VERSION 5.7 ;
  NOWIREEXTENSIONATPIN ON ;
  DIVIDERCHAR "/" ;
  BUSBITCHARS "[]" ;
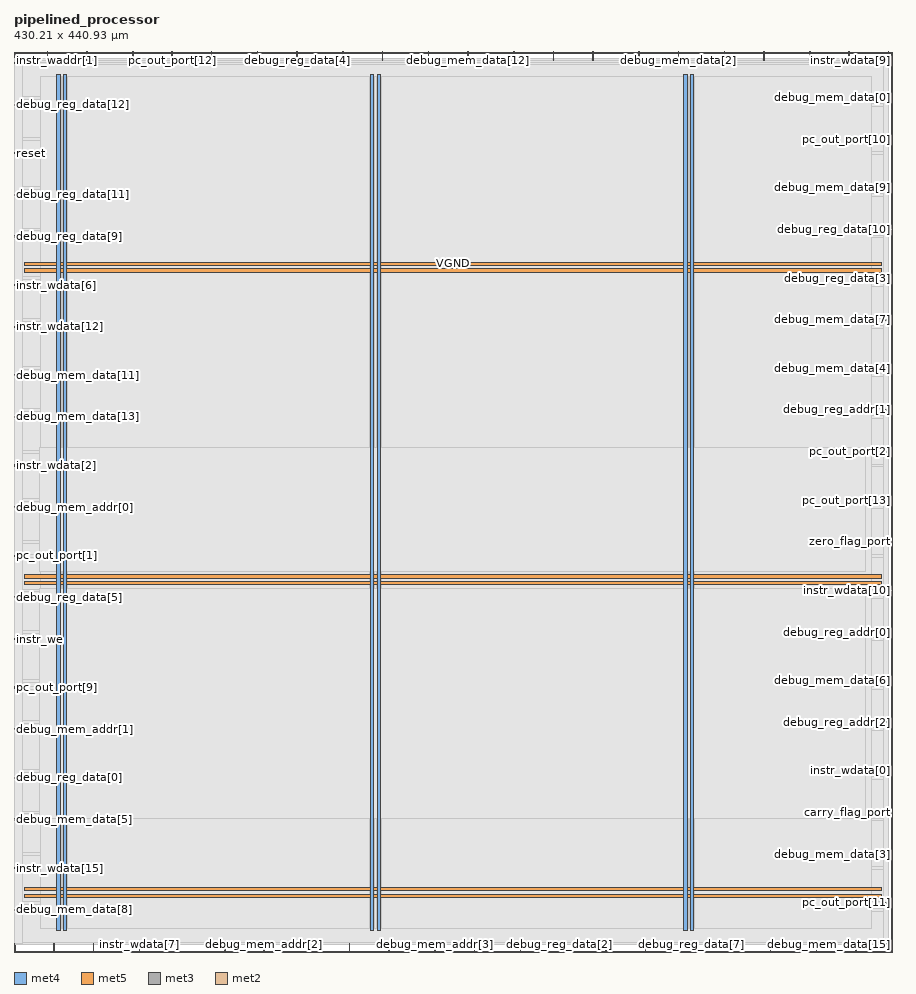
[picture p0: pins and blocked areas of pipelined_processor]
MACRO pipelined_processor
  CLASS BLOCK ;
  FOREIGN pipelined_processor ;
  ORIGIN 0.000 0.000 ;
  SIZE 430.210 BY 440.930 ;
  PIN VGND
    DIRECTION INOUT ;
    USE GROUND ;
    PORT
      LAYER met4 ;
        RECT 24.340 10.640 25.940 430.000 ;
    END
    PORT
      LAYER met4 ;
        RECT 177.940 10.640 179.540 430.000 ;
    END
    PORT
      LAYER met4 ;
        RECT 331.540 10.640 333.140 430.000 ;
    END
    PORT
      LAYER met5 ;
        RECT 5.280 30.030 424.820 31.630 ;
    END
    PORT
      LAYER met5 ;
        RECT 5.280 183.210 424.820 184.810 ;
    END
    PORT
      LAYER met5 ;
        RECT 5.280 336.390 424.820 337.990 ;
    END
  END VGND
  PIN VPWR
    DIRECTION INOUT ;
    USE POWER ;
    PORT
      LAYER met4 ;
        RECT 21.040 10.640 22.640 430.000 ;
    END
    PORT
      LAYER met4 ;
        RECT 174.640 10.640 176.240 430.000 ;
    END
    PORT
      LAYER met4 ;
        RECT 328.240 10.640 329.840 430.000 ;
    END
    PORT
      LAYER met5 ;
        RECT 5.280 26.730 424.820 28.330 ;
    END
    PORT
      LAYER met5 ;
        RECT 5.280 179.910 424.820 181.510 ;
    END
    PORT
      LAYER met5 ;
        RECT 5.280 333.090 424.820 334.690 ;
    END
  END VPWR
  PIN carry_flag_port
    DIRECTION OUTPUT TRISTATE ;
    USE SIGNAL ;
    ANTENNADIFFAREA 0.795200 ;
    PORT
      LAYER met3 ;
        RECT 426.210 68.040 430.210 68.640 ;
    END
  END carry_flag_port
  PIN clk
    DIRECTION INPUT ;
    USE SIGNAL ;
    ANTENNAGATEAREA 1.286700 ;
    ANTENNADIFFAREA 0.434700 ;
    PORT
      LAYER met2 ;
        RECT 389.710 436.930 389.990 440.930 ;
    END
  END clk
  PIN debug_mem_addr[0]
    DIRECTION INPUT ;
    USE SIGNAL ;
    ANTENNAGATEAREA 0.159000 ;
    PORT
      LAYER met3 ;
        RECT 0.000 217.640 4.000 218.240 ;
    END
  END debug_mem_addr[0]
  PIN debug_mem_addr[1]
    DIRECTION INPUT ;
    USE SIGNAL ;
    ANTENNAGATEAREA 0.213000 ;
    PORT
      LAYER met3 ;
        RECT 0.000 108.840 4.000 109.440 ;
    END
  END debug_mem_addr[1]
  PIN debug_mem_addr[2]
    DIRECTION INPUT ;
    USE SIGNAL ;
    ANTENNAGATEAREA 0.159000 ;
    PORT
      LAYER met2 ;
        RECT 122.450 0.000 122.730 4.000 ;
    END
  END debug_mem_addr[2]
  PIN debug_mem_addr[3]
    DIRECTION INPUT ;
    USE SIGNAL ;
    ANTENNAGATEAREA 0.159000 ;
    PORT
      LAYER met2 ;
        RECT 206.170 0.000 206.450 4.000 ;
    END
  END debug_mem_addr[3]
  PIN debug_mem_addr[4]
    DIRECTION INPUT ;
    USE SIGNAL ;
    ANTENNAGATEAREA 0.213000 ;
    PORT
      LAYER met2 ;
        RECT 351.070 0.000 351.350 4.000 ;
    END
  END debug_mem_addr[4]
  PIN debug_mem_addr[5]
    DIRECTION INPUT ;
    USE SIGNAL ;
    ANTENNAGATEAREA 0.159000 ;
    PORT
      LAYER met2 ;
        RECT 370.390 0.000 370.670 4.000 ;
    END
  END debug_mem_addr[5]
  PIN debug_mem_data[0]
    DIRECTION OUTPUT TRISTATE ;
    USE SIGNAL ;
    ANTENNADIFFAREA 0.445500 ;
    PORT
      LAYER met3 ;
        RECT 426.210 418.240 430.210 418.840 ;
    END
  END debug_mem_data[0]
  PIN debug_mem_data[10]
    DIRECTION OUTPUT TRISTATE ;
    USE SIGNAL ;
    ANTENNADIFFAREA 0.445500 ;
    PORT
      LAYER met2 ;
        RECT 58.050 436.930 58.330 440.930 ;
    END
  END debug_mem_data[10]
  PIN debug_mem_data[11]
    DIRECTION OUTPUT TRISTATE ;
    USE SIGNAL ;
    ANTENNADIFFAREA 0.795200 ;
    PORT
      LAYER met3 ;
        RECT 0.000 282.240 4.000 282.840 ;
    END
  END debug_mem_data[11]
  PIN debug_mem_data[12]
    DIRECTION OUTPUT TRISTATE ;
    USE SIGNAL ;
    ANTENNADIFFAREA 0.795200 ;
    PORT
      LAYER met2 ;
        RECT 222.270 436.930 222.550 440.930 ;
    END
  END debug_mem_data[12]
  PIN debug_mem_data[13]
    DIRECTION OUTPUT TRISTATE ;
    USE SIGNAL ;
    ANTENNADIFFAREA 0.795200 ;
    PORT
      LAYER met3 ;
        RECT 0.000 261.840 4.000 262.440 ;
    END
  END debug_mem_data[13]
  PIN debug_mem_data[14]
    DIRECTION OUTPUT TRISTATE ;
    USE SIGNAL ;
    ANTENNADIFFAREA 0.795200 ;
    PORT
      LAYER met3 ;
        RECT 426.210 3.440 430.210 4.040 ;
    END
  END debug_mem_data[14]
  PIN debug_mem_data[15]
    DIRECTION OUTPUT TRISTATE ;
    USE SIGNAL ;
    ANTENNADIFFAREA 0.795200 ;
    PORT
      LAYER met2 ;
        RECT 412.250 0.000 412.530 4.000 ;
    END
  END debug_mem_data[15]
  PIN debug_mem_data[1]
    DIRECTION OUTPUT TRISTATE ;
    USE SIGNAL ;
    ANTENNADIFFAREA 0.445500 ;
    PORT
      LAYER met2 ;
        RECT 244.810 436.930 245.090 440.930 ;
    END
  END debug_mem_data[1]
  PIN debug_mem_data[2]
    DIRECTION OUTPUT TRISTATE ;
    USE SIGNAL ;
    ANTENNADIFFAREA 0.795200 ;
    PORT
      LAYER met2 ;
        RECT 325.310 436.930 325.590 440.930 ;
    END
  END debug_mem_data[2]
  PIN debug_mem_data[3]
    DIRECTION OUTPUT TRISTATE ;
    USE SIGNAL ;
    ANTENNADIFFAREA 0.795200 ;
    PORT
      LAYER met3 ;
        RECT 426.210 47.640 430.210 48.240 ;
    END
  END debug_mem_data[3]
  PIN debug_mem_data[4]
    DIRECTION OUTPUT TRISTATE ;
    USE SIGNAL ;
    ANTENNADIFFAREA 0.445500 ;
    PORT
      LAYER met3 ;
        RECT 426.210 285.640 430.210 286.240 ;
    END
  END debug_mem_data[4]
  PIN debug_mem_data[5]
    DIRECTION OUTPUT TRISTATE ;
    USE SIGNAL ;
    ANTENNADIFFAREA 0.795200 ;
    PORT
      LAYER met3 ;
        RECT 0.000 64.640 4.000 65.240 ;
    END
  END debug_mem_data[5]
  PIN debug_mem_data[6]
    DIRECTION OUTPUT TRISTATE ;
    USE SIGNAL ;
    ANTENNADIFFAREA 0.795200 ;
    PORT
      LAYER met3 ;
        RECT 426.210 132.640 430.210 133.240 ;
    END
  END debug_mem_data[6]
  PIN debug_mem_data[7]
    DIRECTION OUTPUT TRISTATE ;
    USE SIGNAL ;
    ANTENNADIFFAREA 0.795200 ;
    PORT
      LAYER met3 ;
        RECT 426.210 309.440 430.210 310.040 ;
    END
  END debug_mem_data[7]
  PIN debug_mem_data[8]
    DIRECTION OUTPUT TRISTATE ;
    USE SIGNAL ;
    ANTENNADIFFAREA 0.795200 ;
    PORT
      LAYER met3 ;
        RECT 0.000 20.440 4.000 21.040 ;
    END
  END debug_mem_data[8]
  PIN debug_mem_data[9]
    DIRECTION OUTPUT TRISTATE ;
    USE SIGNAL ;
    ANTENNADIFFAREA 0.445500 ;
    PORT
      LAYER met3 ;
        RECT 426.210 374.040 430.210 374.640 ;
    END
  END debug_mem_data[9]
  PIN debug_reg_addr[0]
    DIRECTION INPUT ;
    USE SIGNAL ;
    ANTENNAGATEAREA 0.213000 ;
    PORT
      LAYER met3 ;
        RECT 426.210 156.440 430.210 157.040 ;
    END
  END debug_reg_addr[0]
  PIN debug_reg_addr[1]
    DIRECTION INPUT ;
    USE SIGNAL ;
    ANTENNAGATEAREA 0.213000 ;
    PORT
      LAYER met3 ;
        RECT 426.210 265.240 430.210 265.840 ;
    END
  END debug_reg_addr[1]
  PIN debug_reg_addr[2]
    DIRECTION INPUT ;
    USE SIGNAL ;
    ANTENNAGATEAREA 0.247500 ;
    PORT
      LAYER met3 ;
        RECT 426.210 112.240 430.210 112.840 ;
    END
  END debug_reg_addr[2]
  PIN debug_reg_data[0]
    DIRECTION OUTPUT TRISTATE ;
    USE SIGNAL ;
    ANTENNADIFFAREA 0.795200 ;
    PORT
      LAYER met3 ;
        RECT 0.000 85.040 4.000 85.640 ;
    END
  END debug_reg_data[0]
  PIN debug_reg_data[10]
    DIRECTION OUTPUT TRISTATE ;
    USE SIGNAL ;
    ANTENNADIFFAREA 0.445500 ;
    PORT
      LAYER met3 ;
        RECT 426.210 353.640 430.210 354.240 ;
    END
  END debug_reg_data[10]
  PIN debug_reg_data[11]
    DIRECTION OUTPUT TRISTATE ;
    USE SIGNAL ;
    ANTENNADIFFAREA 0.795200 ;
    PORT
      LAYER met3 ;
        RECT 0.000 370.640 4.000 371.240 ;
    END
  END debug_reg_data[11]
  PIN debug_reg_data[12]
    DIRECTION OUTPUT TRISTATE ;
    USE SIGNAL ;
    ANTENNADIFFAREA 0.795200 ;
    PORT
      LAYER met3 ;
        RECT 0.000 414.840 4.000 415.440 ;
    END
  END debug_reg_data[12]
  PIN debug_reg_data[13]
    DIRECTION OUTPUT TRISTATE ;
    USE SIGNAL ;
    ANTENNADIFFAREA 0.795200 ;
    PORT
      LAYER met3 ;
        RECT 0.000 435.240 4.000 435.840 ;
    END
  END debug_reg_data[13]
  PIN debug_reg_data[14]
    DIRECTION OUTPUT TRISTATE ;
    USE SIGNAL ;
    ANTENNADIFFAREA 0.795200 ;
    PORT
      LAYER met2 ;
        RECT 38.730 0.000 39.010 4.000 ;
    END
  END debug_reg_data[14]
  PIN debug_reg_data[15]
    DIRECTION OUTPUT TRISTATE ;
    USE SIGNAL ;
    ANTENNADIFFAREA 0.795200 ;
    PORT
      LAYER met2 ;
        RECT 264.130 436.930 264.410 440.930 ;
    END
  END debug_reg_data[15]
  PIN debug_reg_data[1]
    DIRECTION OUTPUT TRISTATE ;
    USE SIGNAL ;
    ANTENNADIFFAREA 0.795200 ;
    PORT
      LAYER met2 ;
        RECT 164.310 0.000 164.590 4.000 ;
    END
  END debug_reg_data[1]
  PIN debug_reg_data[2]
    DIRECTION OUTPUT TRISTATE ;
    USE SIGNAL ;
    ANTENNADIFFAREA 0.795200 ;
    PORT
      LAYER met2 ;
        RECT 267.350 0.000 267.630 4.000 ;
    END
  END debug_reg_data[2]
  PIN debug_reg_data[3]
    DIRECTION OUTPUT TRISTATE ;
    USE SIGNAL ;
    ANTENNADIFFAREA 0.445500 ;
    PORT
      LAYER met3 ;
        RECT 426.210 329.840 430.210 330.440 ;
    END
  END debug_reg_data[3]
  PIN debug_reg_data[4]
    DIRECTION OUTPUT TRISTATE ;
    USE SIGNAL ;
    ANTENNADIFFAREA 0.795200 ;
    PORT
      LAYER met2 ;
        RECT 138.550 436.930 138.830 440.930 ;
    END
  END debug_reg_data[4]
  PIN debug_reg_data[5]
    DIRECTION OUTPUT TRISTATE ;
    USE SIGNAL ;
    ANTENNADIFFAREA 0.795200 ;
    PORT
      LAYER met3 ;
        RECT 0.000 173.440 4.000 174.040 ;
    END
  END debug_reg_data[5]
  PIN debug_reg_data[6]
    DIRECTION OUTPUT TRISTATE ;
    USE SIGNAL ;
    ANTENNADIFFAREA 0.795200 ;
    PORT
      LAYER met2 ;
        RECT 103.130 0.000 103.410 4.000 ;
    END
  END debug_reg_data[6]
  PIN debug_reg_data[7]
    DIRECTION OUTPUT TRISTATE ;
    USE SIGNAL ;
    ANTENNADIFFAREA 0.795200 ;
    PORT
      LAYER met2 ;
        RECT 331.750 0.000 332.030 4.000 ;
    END
  END debug_reg_data[7]
  PIN debug_reg_data[8]
    DIRECTION OUTPUT TRISTATE ;
    USE SIGNAL ;
    ANTENNADIFFAREA 0.445500 ;
    PORT
      LAYER met2 ;
        RECT 305.990 436.930 306.270 440.930 ;
    END
  END debug_reg_data[8]
  PIN debug_reg_data[9]
    DIRECTION OUTPUT TRISTATE ;
    USE SIGNAL ;
    ANTENNADIFFAREA 0.795200 ;
    PORT
      LAYER met3 ;
        RECT 0.000 350.240 4.000 350.840 ;
    END
  END debug_reg_data[9]
  PIN instr_waddr[0]
    DIRECTION INPUT ;
    USE SIGNAL ;
    ANTENNAGATEAREA 0.213000 ;
    PORT
      LAYER met2 ;
        RECT 248.030 0.000 248.310 4.000 ;
    END
  END instr_waddr[0]
  PIN instr_waddr[1]
    DIRECTION INPUT ;
    USE SIGNAL ;
    ANTENNAGATEAREA 0.159000 ;
    PORT
      LAYER met2 ;
        RECT 16.190 436.930 16.470 440.930 ;
    END
  END instr_waddr[1]
  PIN instr_waddr[2]
    DIRECTION INPUT ;
    USE SIGNAL ;
    ANTENNAGATEAREA 0.426000 ;
    PORT
      LAYER met2 ;
        RECT 392.930 0.000 393.210 4.000 ;
    END
  END instr_waddr[2]
  PIN instr_waddr[3]
    DIRECTION INPUT ;
    USE SIGNAL ;
    ANTENNAGATEAREA 0.213000 ;
    PORT
      LAYER met2 ;
        RECT 161.090 436.930 161.370 440.930 ;
    END
  END instr_waddr[3]
  PIN instr_wdata[0]
    DIRECTION INPUT ;
    USE SIGNAL ;
    ANTENNAGATEAREA 0.126000 ;
    PORT
      LAYER met3 ;
        RECT 426.210 88.440 430.210 89.040 ;
    END
  END instr_wdata[0]
  PIN instr_wdata[10]
    DIRECTION INPUT ;
    USE SIGNAL ;
    ANTENNAGATEAREA 0.126000 ;
    PORT
      LAYER met3 ;
        RECT 426.210 176.840 430.210 177.440 ;
    END
  END instr_wdata[10]
  PIN instr_wdata[11]
    DIRECTION INPUT ;
    USE SIGNAL ;
    ANTENNAGATEAREA 0.126000 ;
    PORT
      LAYER met2 ;
        RECT 309.210 0.000 309.490 4.000 ;
    END
  END instr_wdata[11]
  PIN instr_wdata[12]
    DIRECTION INPUT ;
    USE SIGNAL ;
    ANTENNAGATEAREA 0.126000 ;
    PORT
      LAYER met3 ;
        RECT 0.000 306.040 4.000 306.640 ;
    END
  END instr_wdata[12]
  PIN instr_wdata[13]
    DIRECTION INPUT ;
    USE SIGNAL ;
    ANTENNAGATEAREA 0.126000 ;
    PORT
      LAYER met2 ;
        RECT 119.230 436.930 119.510 440.930 ;
    END
  END instr_wdata[13]
  PIN instr_wdata[14]
    DIRECTION INPUT ;
    USE SIGNAL ;
    ANTENNAGATEAREA 0.126000 ;
    PORT
      LAYER met2 ;
        RECT 202.950 436.930 203.230 440.930 ;
    END
  END instr_wdata[14]
  PIN instr_wdata[15]
    DIRECTION INPUT ;
    USE SIGNAL ;
    ANTENNAGATEAREA 0.126000 ;
    PORT
      LAYER met3 ;
        RECT 0.000 40.840 4.000 41.440 ;
    END
  END instr_wdata[15]
  PIN instr_wdata[1]
    DIRECTION INPUT ;
    USE SIGNAL ;
    ANTENNAGATEAREA 0.126000 ;
    PORT
      LAYER met2 ;
        RECT 0.090 0.000 0.370 4.000 ;
    END
  END instr_wdata[1]
  PIN instr_wdata[2]
    DIRECTION INPUT ;
    USE SIGNAL ;
    ANTENNAGATEAREA 0.126000 ;
    PORT
      LAYER met3 ;
        RECT 0.000 238.040 4.000 238.640 ;
    END
  END instr_wdata[2]
  PIN instr_wdata[3]
    DIRECTION INPUT ;
    USE SIGNAL ;
    ANTENNAGATEAREA 0.126000 ;
    PORT
      LAYER met2 ;
        RECT 180.410 436.930 180.690 440.930 ;
    END
  END instr_wdata[3]
  PIN instr_wdata[4]
    DIRECTION INPUT ;
    USE SIGNAL ;
    ANTENNAGATEAREA 0.126000 ;
    PORT
      LAYER met2 ;
        RECT 283.450 436.930 283.730 440.930 ;
    END
  END instr_wdata[4]
  PIN instr_wdata[5]
    DIRECTION INPUT ;
    USE SIGNAL ;
    ANTENNAGATEAREA 0.126000 ;
    PORT
      LAYER met2 ;
        RECT 409.030 436.930 409.310 440.930 ;
    END
  END instr_wdata[5]
  PIN instr_wdata[6]
    DIRECTION INPUT ;
    USE SIGNAL ;
    ANTENNAGATEAREA 0.126000 ;
    PORT
      LAYER met3 ;
        RECT 0.000 326.440 4.000 327.040 ;
    END
  END instr_wdata[6]
  PIN instr_wdata[7]
    DIRECTION INPUT ;
    USE SIGNAL ;
    ANTENNAGATEAREA 0.126000 ;
    PORT
      LAYER met2 ;
        RECT 61.270 0.000 61.550 4.000 ;
    END
  END instr_wdata[7]
  PIN instr_wdata[8]
    DIRECTION INPUT ;
    USE SIGNAL ;
    ANTENNAGATEAREA 0.126000 ;
    PORT
      LAYER met2 ;
        RECT 19.410 0.000 19.690 4.000 ;
    END
  END instr_wdata[8]
  PIN instr_wdata[9]
    DIRECTION INPUT ;
    USE SIGNAL ;
    ANTENNAGATEAREA 0.126000 ;
    PORT
      LAYER met2 ;
        RECT 428.350 436.930 428.630 440.930 ;
    END
  END instr_wdata[9]
  PIN instr_we
    DIRECTION INPUT ;
    USE SIGNAL ;
    ANTENNAGATEAREA 0.213000 ;
    PORT
      LAYER met3 ;
        RECT 0.000 153.040 4.000 153.640 ;
    END
  END instr_we
  PIN pc_out_port[0]
    DIRECTION OUTPUT TRISTATE ;
    USE SIGNAL ;
    ANTENNADIFFAREA 0.795200 ;
    PORT
      LAYER met2 ;
        RECT 183.630 0.000 183.910 4.000 ;
    END
  END pc_out_port[0]
  PIN pc_out_port[10]
    DIRECTION OUTPUT TRISTATE ;
    USE SIGNAL ;
    ANTENNADIFFAREA 0.445500 ;
    PORT
      LAYER met3 ;
        RECT 426.210 397.840 430.210 398.440 ;
    END
  END pc_out_port[10]
  PIN pc_out_port[11]
    DIRECTION OUTPUT TRISTATE ;
    USE SIGNAL ;
    ANTENNADIFFAREA 0.445500 ;
    PORT
      LAYER met3 ;
        RECT 426.210 23.840 430.210 24.440 ;
    END
  END pc_out_port[11]
  PIN pc_out_port[12]
    DIRECTION OUTPUT TRISTATE ;
    USE SIGNAL ;
    ANTENNADIFFAREA 0.795200 ;
    PORT
      LAYER met2 ;
        RECT 77.370 436.930 77.650 440.930 ;
    END
  END pc_out_port[12]
  PIN pc_out_port[13]
    DIRECTION OUTPUT TRISTATE ;
    USE SIGNAL ;
    ANTENNADIFFAREA 0.795200 ;
    PORT
      LAYER met3 ;
        RECT 426.210 221.040 430.210 221.640 ;
    END
  END pc_out_port[13]
  PIN pc_out_port[14]
    DIRECTION OUTPUT TRISTATE ;
    USE SIGNAL ;
    ANTENNADIFFAREA 0.795200 ;
    PORT
      LAYER met2 ;
        RECT 80.590 0.000 80.870 4.000 ;
    END
  END pc_out_port[14]
  PIN pc_out_port[15]
    DIRECTION OUTPUT TRISTATE ;
    USE SIGNAL ;
    ANTENNADIFFAREA 0.795200 ;
    PORT
      LAYER met2 ;
        RECT 144.990 0.000 145.270 4.000 ;
    END
  END pc_out_port[15]
  PIN pc_out_port[1]
    DIRECTION OUTPUT TRISTATE ;
    USE SIGNAL ;
    ANTENNADIFFAREA 0.795200 ;
    PORT
      LAYER met3 ;
        RECT 0.000 193.840 4.000 194.440 ;
    END
  END pc_out_port[1]
  PIN pc_out_port[2]
    DIRECTION OUTPUT TRISTATE ;
    USE SIGNAL ;
    ANTENNADIFFAREA 0.445500 ;
    PORT
      LAYER met3 ;
        RECT 426.210 244.840 430.210 245.440 ;
    END
  END pc_out_port[2]
  PIN pc_out_port[3]
    DIRECTION OUTPUT TRISTATE ;
    USE SIGNAL ;
    ANTENNADIFFAREA 0.795200 ;
    PORT
      LAYER met2 ;
        RECT 225.490 0.000 225.770 4.000 ;
    END
  END pc_out_port[3]
  PIN pc_out_port[4]
    DIRECTION OUTPUT TRISTATE ;
    USE SIGNAL ;
    ANTENNADIFFAREA 0.445500 ;
    PORT
      LAYER met2 ;
        RECT 367.170 436.930 367.450 440.930 ;
    END
  END pc_out_port[4]
  PIN pc_out_port[5]
    DIRECTION OUTPUT TRISTATE ;
    USE SIGNAL ;
    ANTENNADIFFAREA 0.445500 ;
    PORT
      LAYER met2 ;
        RECT 347.850 436.930 348.130 440.930 ;
    END
  END pc_out_port[5]
  PIN pc_out_port[6]
    DIRECTION OUTPUT TRISTATE ;
    USE SIGNAL ;
    ANTENNADIFFAREA 0.795200 ;
    PORT
      LAYER met2 ;
        RECT 35.510 436.930 35.790 440.930 ;
    END
  END pc_out_port[6]
  PIN pc_out_port[7]
    DIRECTION OUTPUT TRISTATE ;
    USE SIGNAL ;
    ANTENNADIFFAREA 0.795200 ;
    PORT
      LAYER met2 ;
        RECT 96.690 436.930 96.970 440.930 ;
    END
  END pc_out_port[7]
  PIN pc_out_port[8]
    DIRECTION OUTPUT TRISTATE ;
    USE SIGNAL ;
    ANTENNADIFFAREA 0.795200 ;
    PORT
      LAYER met2 ;
        RECT 289.890 0.000 290.170 4.000 ;
    END
  END pc_out_port[8]
  PIN pc_out_port[9]
    DIRECTION OUTPUT TRISTATE ;
    USE SIGNAL ;
    ANTENNADIFFAREA 0.795200 ;
    PORT
      LAYER met3 ;
        RECT 0.000 129.240 4.000 129.840 ;
    END
  END pc_out_port[9]
  PIN reset
    DIRECTION INPUT ;
    USE SIGNAL ;
    ANTENNAGATEAREA 0.213000 ;
    PORT
      LAYER met3 ;
        RECT 0.000 391.040 4.000 391.640 ;
    END
  END reset
  PIN zero_flag_port
    DIRECTION OUTPUT TRISTATE ;
    USE SIGNAL ;
    ANTENNADIFFAREA 0.795200 ;
    PORT
      LAYER met3 ;
        RECT 426.210 200.640 430.210 201.240 ;
    END
  END zero_flag_port
  OBS
      LAYER li1 ;
        RECT 5.520 10.795 424.580 429.845 ;
      LAYER met1 ;
        RECT 0.070 8.540 428.650 431.760 ;
      LAYER met2 ;
        RECT 0.100 436.650 15.910 437.650 ;
        RECT 16.750 436.650 35.230 437.650 ;
        RECT 36.070 436.650 57.770 437.650 ;
        RECT 58.610 436.650 77.090 437.650 ;
        RECT 77.930 436.650 96.410 437.650 ;
        RECT 97.250 436.650 118.950 437.650 ;
        RECT 119.790 436.650 138.270 437.650 ;
        RECT 139.110 436.650 160.810 437.650 ;
        RECT 161.650 436.650 180.130 437.650 ;
        RECT 180.970 436.650 202.670 437.650 ;
        RECT 203.510 436.650 221.990 437.650 ;
        RECT 222.830 436.650 244.530 437.650 ;
        RECT 245.370 436.650 263.850 437.650 ;
        RECT 264.690 436.650 283.170 437.650 ;
        RECT 284.010 436.650 305.710 437.650 ;
        RECT 306.550 436.650 325.030 437.650 ;
        RECT 325.870 436.650 347.570 437.650 ;
        RECT 348.410 436.650 366.890 437.650 ;
        RECT 367.730 436.650 389.430 437.650 ;
        RECT 390.270 436.650 408.750 437.650 ;
        RECT 409.590 436.650 428.070 437.650 ;
        RECT 0.100 4.280 428.620 436.650 ;
        RECT 0.650 3.555 19.130 4.280 ;
        RECT 19.970 3.555 38.450 4.280 ;
        RECT 39.290 3.555 60.990 4.280 ;
        RECT 61.830 3.555 80.310 4.280 ;
        RECT 81.150 3.555 102.850 4.280 ;
        RECT 103.690 3.555 122.170 4.280 ;
        RECT 123.010 3.555 144.710 4.280 ;
        RECT 145.550 3.555 164.030 4.280 ;
        RECT 164.870 3.555 183.350 4.280 ;
        RECT 184.190 3.555 205.890 4.280 ;
        RECT 206.730 3.555 225.210 4.280 ;
        RECT 226.050 3.555 247.750 4.280 ;
        RECT 248.590 3.555 267.070 4.280 ;
        RECT 267.910 3.555 289.610 4.280 ;
        RECT 290.450 3.555 308.930 4.280 ;
        RECT 309.770 3.555 331.470 4.280 ;
        RECT 332.310 3.555 350.790 4.280 ;
        RECT 351.630 3.555 370.110 4.280 ;
        RECT 370.950 3.555 392.650 4.280 ;
        RECT 393.490 3.555 411.970 4.280 ;
        RECT 412.810 3.555 428.620 4.280 ;
      LAYER met3 ;
        RECT 4.400 434.840 426.210 435.705 ;
        RECT 3.990 419.240 426.210 434.840 ;
        RECT 3.990 417.840 425.810 419.240 ;
        RECT 3.990 415.840 426.210 417.840 ;
        RECT 4.400 414.440 426.210 415.840 ;
        RECT 3.990 398.840 426.210 414.440 ;
        RECT 3.990 397.440 425.810 398.840 ;
        RECT 3.990 392.040 426.210 397.440 ;
        RECT 4.400 390.640 426.210 392.040 ;
        RECT 3.990 375.040 426.210 390.640 ;
        RECT 3.990 373.640 425.810 375.040 ;
        RECT 3.990 371.640 426.210 373.640 ;
        RECT 4.400 370.240 426.210 371.640 ;
        RECT 3.990 354.640 426.210 370.240 ;
        RECT 3.990 353.240 425.810 354.640 ;
        RECT 3.990 351.240 426.210 353.240 ;
        RECT 4.400 349.840 426.210 351.240 ;
        RECT 3.990 330.840 426.210 349.840 ;
        RECT 3.990 329.440 425.810 330.840 ;
        RECT 3.990 327.440 426.210 329.440 ;
        RECT 4.400 326.040 426.210 327.440 ;
        RECT 3.990 310.440 426.210 326.040 ;
        RECT 3.990 309.040 425.810 310.440 ;
        RECT 3.990 307.040 426.210 309.040 ;
        RECT 4.400 305.640 426.210 307.040 ;
        RECT 3.990 286.640 426.210 305.640 ;
        RECT 3.990 285.240 425.810 286.640 ;
        RECT 3.990 283.240 426.210 285.240 ;
        RECT 4.400 281.840 426.210 283.240 ;
        RECT 3.990 266.240 426.210 281.840 ;
        RECT 3.990 264.840 425.810 266.240 ;
        RECT 3.990 262.840 426.210 264.840 ;
        RECT 4.400 261.440 426.210 262.840 ;
        RECT 3.990 245.840 426.210 261.440 ;
        RECT 3.990 244.440 425.810 245.840 ;
        RECT 3.990 239.040 426.210 244.440 ;
        RECT 4.400 237.640 426.210 239.040 ;
        RECT 3.990 222.040 426.210 237.640 ;
        RECT 3.990 220.640 425.810 222.040 ;
        RECT 3.990 218.640 426.210 220.640 ;
        RECT 4.400 217.240 426.210 218.640 ;
        RECT 3.990 201.640 426.210 217.240 ;
        RECT 3.990 200.240 425.810 201.640 ;
        RECT 3.990 194.840 426.210 200.240 ;
        RECT 4.400 193.440 426.210 194.840 ;
        RECT 3.990 177.840 426.210 193.440 ;
        RECT 3.990 176.440 425.810 177.840 ;
        RECT 3.990 174.440 426.210 176.440 ;
        RECT 4.400 173.040 426.210 174.440 ;
        RECT 3.990 157.440 426.210 173.040 ;
        RECT 3.990 156.040 425.810 157.440 ;
        RECT 3.990 154.040 426.210 156.040 ;
        RECT 4.400 152.640 426.210 154.040 ;
        RECT 3.990 133.640 426.210 152.640 ;
        RECT 3.990 132.240 425.810 133.640 ;
        RECT 3.990 130.240 426.210 132.240 ;
        RECT 4.400 128.840 426.210 130.240 ;
        RECT 3.990 113.240 426.210 128.840 ;
        RECT 3.990 111.840 425.810 113.240 ;
        RECT 3.990 109.840 426.210 111.840 ;
        RECT 4.400 108.440 426.210 109.840 ;
        RECT 3.990 89.440 426.210 108.440 ;
        RECT 3.990 88.040 425.810 89.440 ;
        RECT 3.990 86.040 426.210 88.040 ;
        RECT 4.400 84.640 426.210 86.040 ;
        RECT 3.990 69.040 426.210 84.640 ;
        RECT 3.990 67.640 425.810 69.040 ;
        RECT 3.990 65.640 426.210 67.640 ;
        RECT 4.400 64.240 426.210 65.640 ;
        RECT 3.990 48.640 426.210 64.240 ;
        RECT 3.990 47.240 425.810 48.640 ;
        RECT 3.990 41.840 426.210 47.240 ;
        RECT 4.400 40.440 426.210 41.840 ;
        RECT 3.990 24.840 426.210 40.440 ;
        RECT 3.990 23.440 425.810 24.840 ;
        RECT 3.990 21.440 426.210 23.440 ;
        RECT 4.400 20.040 426.210 21.440 ;
        RECT 3.990 4.440 426.210 20.040 ;
        RECT 3.990 3.575 425.810 4.440 ;
      LAYER met4 ;
        RECT 12.750 11.735 20.640 428.905 ;
        RECT 23.040 11.735 23.940 428.905 ;
        RECT 26.340 11.735 174.240 428.905 ;
        RECT 176.640 11.735 177.540 428.905 ;
        RECT 179.940 11.735 327.840 428.905 ;
        RECT 330.240 11.735 331.140 428.905 ;
        RECT 333.540 11.735 420.145 428.905 ;
      LAYER met5 ;
        RECT 12.540 186.410 417.100 247.300 ;
        RECT 12.540 65.500 417.100 178.310 ;
  END
END pipelined_processor
END LIBRARY

